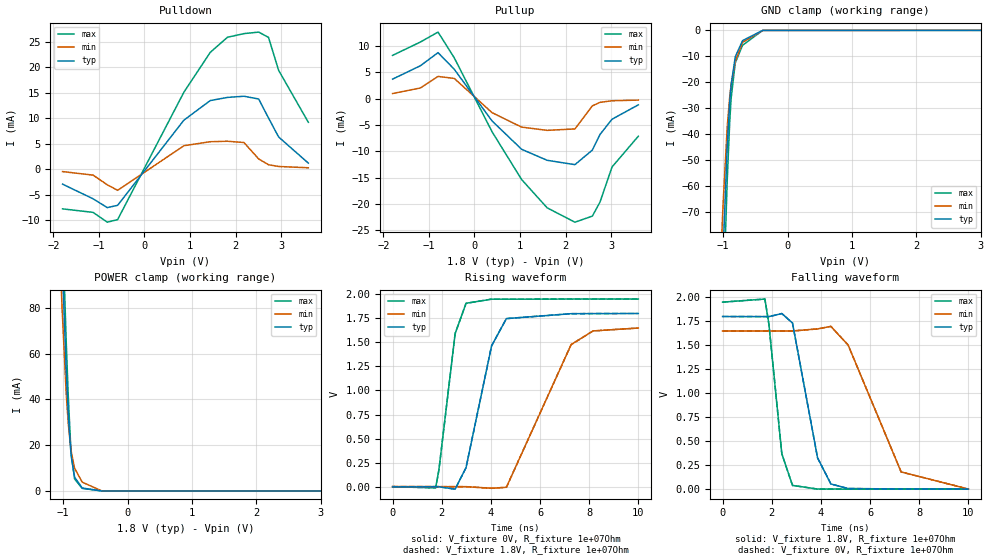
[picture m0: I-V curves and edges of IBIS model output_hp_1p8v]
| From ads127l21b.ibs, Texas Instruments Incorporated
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|   output_hp_1p8v Model
[Model]   output_hp_1p8v
Model_type   3-state
Polarity   Non-Inverting
Vmeas = 0.9
Vref = 0
Cref = 2pF
Rref = 100000
|   typ   min   max
C_comp   1.60pF   1.01pF   1.60pF
[Voltage Range]   1.8   1.65   1.95
[Temperature Range]   25   125   -40
[Pullup Reference]   1.8   1.65   1.95
[Pulldown Reference]   -0   0   0
[Power Clamp Reference]   1.8   1.65   1.95
[GND Clamp Reference]   0   0   0
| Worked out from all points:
|   slope of the pulldown table from 0 to 0.27 V, typ, clamps not added: 79.6 ohm
|   slope of the pullup table from 0 to 0.27 V, typ, clamps not added: 88.9 ohm
|   falling waveform, V_fixture 1.8V, R_fixture 1e+07Ohm: 20-80 % time 762ps typ, 1.49ns min, 452ps max; typ from 1.8 V to 0 V
|   rising waveform, V_fixture 0V, R_fixture 1e+07Ohm: 20-80 % time 890ps typ, 1.56ns min, 547ps max; typ from 0 V to 1.8 V
|   rising waveform, V_fixture 1.8V, R_fixture 1e+07Ohm: 20-80 % time 890ps typ, 1.56ns min, 547ps max; typ from 0 V to 1.8 V
|   falling waveform, V_fixture 0V, R_fixture 1e+07Ohm: 20-80 % time 762ps typ, 1.49ns min, 452ps max; typ from 1.8 V to 0 V
[Pulldown]
|   Voltage   I(typ)   I(min)   I(max)
-1.8V     -2.886mA   -423.5uA   -7.73mA
-1.13V    -5.753mA   -1.117mA   -8.415mA
-817.2mV  -7.485mA   -3.011mA   -10.34mA
-590.4mV  -7.039mA   -4.096mA   -9.833mA
867.6mV   9.67mA     4.647mA    15.16mA
1.445V    13.49mA    5.428mA    22.93mA
1.823V    14.11mA    5.523mA    25.9mA
2.185V    14.34mA    5.272mA    26.61mA
2.509V    13.8mA     2.053mA    26.91mA
2.725V    10.08mA    917.6uA    25.87mA
2.947V    6.36mA     577.1uA    19.42mA
3.6V      1.234mA    324.1uA    9.233mA
[GND Clamp]
|   Voltage   I(typ)   I(min)   I(max)
-1.8V     -864.5mA   -803.3mA   -907.6mA
-1.076V   -146.6mA   -117mA     -174.4mA
-1.039V   -114.9mA   -90.36mA   -140mA
-1.012V   -93.71mA   -73.31mA   -116.3mA
-1.001V   -85.64mA   -67.03mA   -107.1mA
-936mV    -44.28mA   -36.96mA   -57.4mA
-898.2mV  -27.72mA   -25.68mA   -35.42mA
-876.6mV  -21.1mA    -21mA      -26.33mA
-811.8mV  -10.22mA   -11.93mA   -12.55mA
-698.4mV  -3.962mA   -4.625mA   -5.764mA
-385.2mV  -27.8uA    -39.47uA   -29.6uA
3.6V      0A         0A         0A
[Pullup]
|   Voltage   I(typ)   I(min)   I(max)
-1.8V     3.687mA    949.6uA    8.187mA
-1.19V    6.214mA    2.005mA    10.72mA
-801mV    8.71mA     4.195mA    12.61mA
-444.6mV  5.551mA    3.817mA    7.726mA
387mV     -4.26mA    -2.685mA   -6.315mA
1.035V    -9.626mA   -5.419mA   -15.36mA
1.597V    -11.72mA   -6.037mA   -20.74mA
2.207V    -12.54mA   -5.765mA   -23.46mA
2.59V     -9.778mA   -1.383mA   -22.3mA
2.758V    -6.81mA    -724.1uA   -19.64mA
3.022V    -3.917mA   -422.1uA   -12.98mA
3.6V      -1.191mA   -292.2uA   -7.146mA
[POWER Clamp]
|   Voltage   I(typ)   I(min)   I(max)
-1.8V     906.2mA    854.7mA    940.6mA
-1.098V   176.9mA    144mA      201mA
-1.049V   131.4mA    104mA      153.1mA
-1.017V   102.7mA    80.12mA    122.2mA
-952.2mV  52.48mA    42.27mA    65.03mA
-919.8mV  33.26mA    29.27mA    40.95mA
-887.4mV  19.39mA    20.05mA    22.34mA
-871.2mV  14.49mA    16.65mA    15.66mA
-822.6mV  6.056mA    9.932mA    5.244mA
-703.8mV  1.266mA    3.827mA    1.101mA
-401.4mV  1.156uA    36.32uA    104.9nA
3.6V      0A         0A         0A
[Ramp]
R_load = 1e+07
|   typ   min   max
dV/dt_r   1.07999/8.86791e-10   0.988855/1.54933e-09   1.16999/5.46575e-10
dV/dt_f   1.07999/7.60808e-10   0.988851/1.48023e-09   1.16999/4.50735e-10
[Falling Waveform]
V_fixture = 1.8V
V_fixture_min = 1.65V
V_fixture_max = 1.95V
R_fixture = 1e+07Ohm
C_fixture = 0F
|   Time   V(typ)   V(min)   V(max)
0s        1.8V       1.649V     1.95V
1.722ns   1.799V     1.649V     1.982V
1.885ns   1.799V     1.649V     1.721V
2.411ns   1.831V     1.649V     368.8mV
2.846ns   1.732V     1.649V     38.98mV
3.865ns   327mV      1.671V     983.4uV
4.408ns   53.98mV    1.697V     897.1uV
5.108ns   6.733mV    1.503V     786.1uV
7.266ns   1.594mV    179.6mV    443.9uV
10ns      13.91uV    1.265mV    10.21uV
[Rising Waveform]
V_fixture = 0V
V_fixture_min = 0V
V_fixture_max = 0V
R_fixture = 1e+07Ohm
C_fixture = 0F
|   Time   V(typ)   V(min)   V(max)
0s        76.62nV    1.217mV    1.595nV
1.752ns   -99.07uV   712.9uV    -12mV
1.885ns   -106.6uV   674.6uV    172.9mV
2.546ns   -25.51mV   484.1uV    1.591V
2.99ns    199mV      356.5uV    1.906V
4.029ns   1.464V     -16.46mV   1.949V
4.632ns   1.747V     -5.885mV   1.949V
7.266ns   1.798V     1.477V     1.95V
8.16ns    1.799V     1.619V     1.95V
10ns      1.8V       1.649V     1.95V
[Rising Waveform]
V_fixture = 1.8V
V_fixture_min = 1.65V
V_fixture_max = 1.95V
R_fixture = 1e+07Ohm
C_fixture = 0F
|   Time   V(typ)   V(min)   V(max)
0s        13.88uV    1.24mV     10.21uV
1.752ns   -85.41uV   735.4uV    -11.99mV
1.885ns   -92.96uV   697uV      172.9mV
2.546ns   -25.49mV   506.4uV    1.591V
2.99ns    199.1mV    378.6uV    1.906V
4.029ns   1.464V     -16.43mV   1.949V
4.632ns   1.747V     -5.834mV   1.949V
7.266ns   1.798V     1.477V     1.95V
8.16ns    1.799V     1.619V     1.95V
10ns      1.8V       1.649V     1.95V
[Falling Waveform]
|Gnd
V_fixture = 0V
V_fixture_min = 0V
V_fixture_max = 0V
R_fixture = 1e+07Ohm
C_fixture = 0F
|   Time   V(typ)   V(min)   V(max)
0s        1.8V       1.649V     1.95V
1.722ns   1.799V     1.649V     1.982V
1.885ns   1.799V     1.649V     1.721V
2.411ns   1.831V     1.649V     368.7mV
2.846ns   1.732V     1.649V     38.97mV
3.865ns   327mV      1.671V     973.1uV
4.408ns   53.96mV    1.697V     886.9uV
5.108ns   6.719mV    1.503V     775.9uV
7.266ns   1.581mV    179.6mV    433.7uV
10ns      111.5nV    1.242mV    1.585nV
